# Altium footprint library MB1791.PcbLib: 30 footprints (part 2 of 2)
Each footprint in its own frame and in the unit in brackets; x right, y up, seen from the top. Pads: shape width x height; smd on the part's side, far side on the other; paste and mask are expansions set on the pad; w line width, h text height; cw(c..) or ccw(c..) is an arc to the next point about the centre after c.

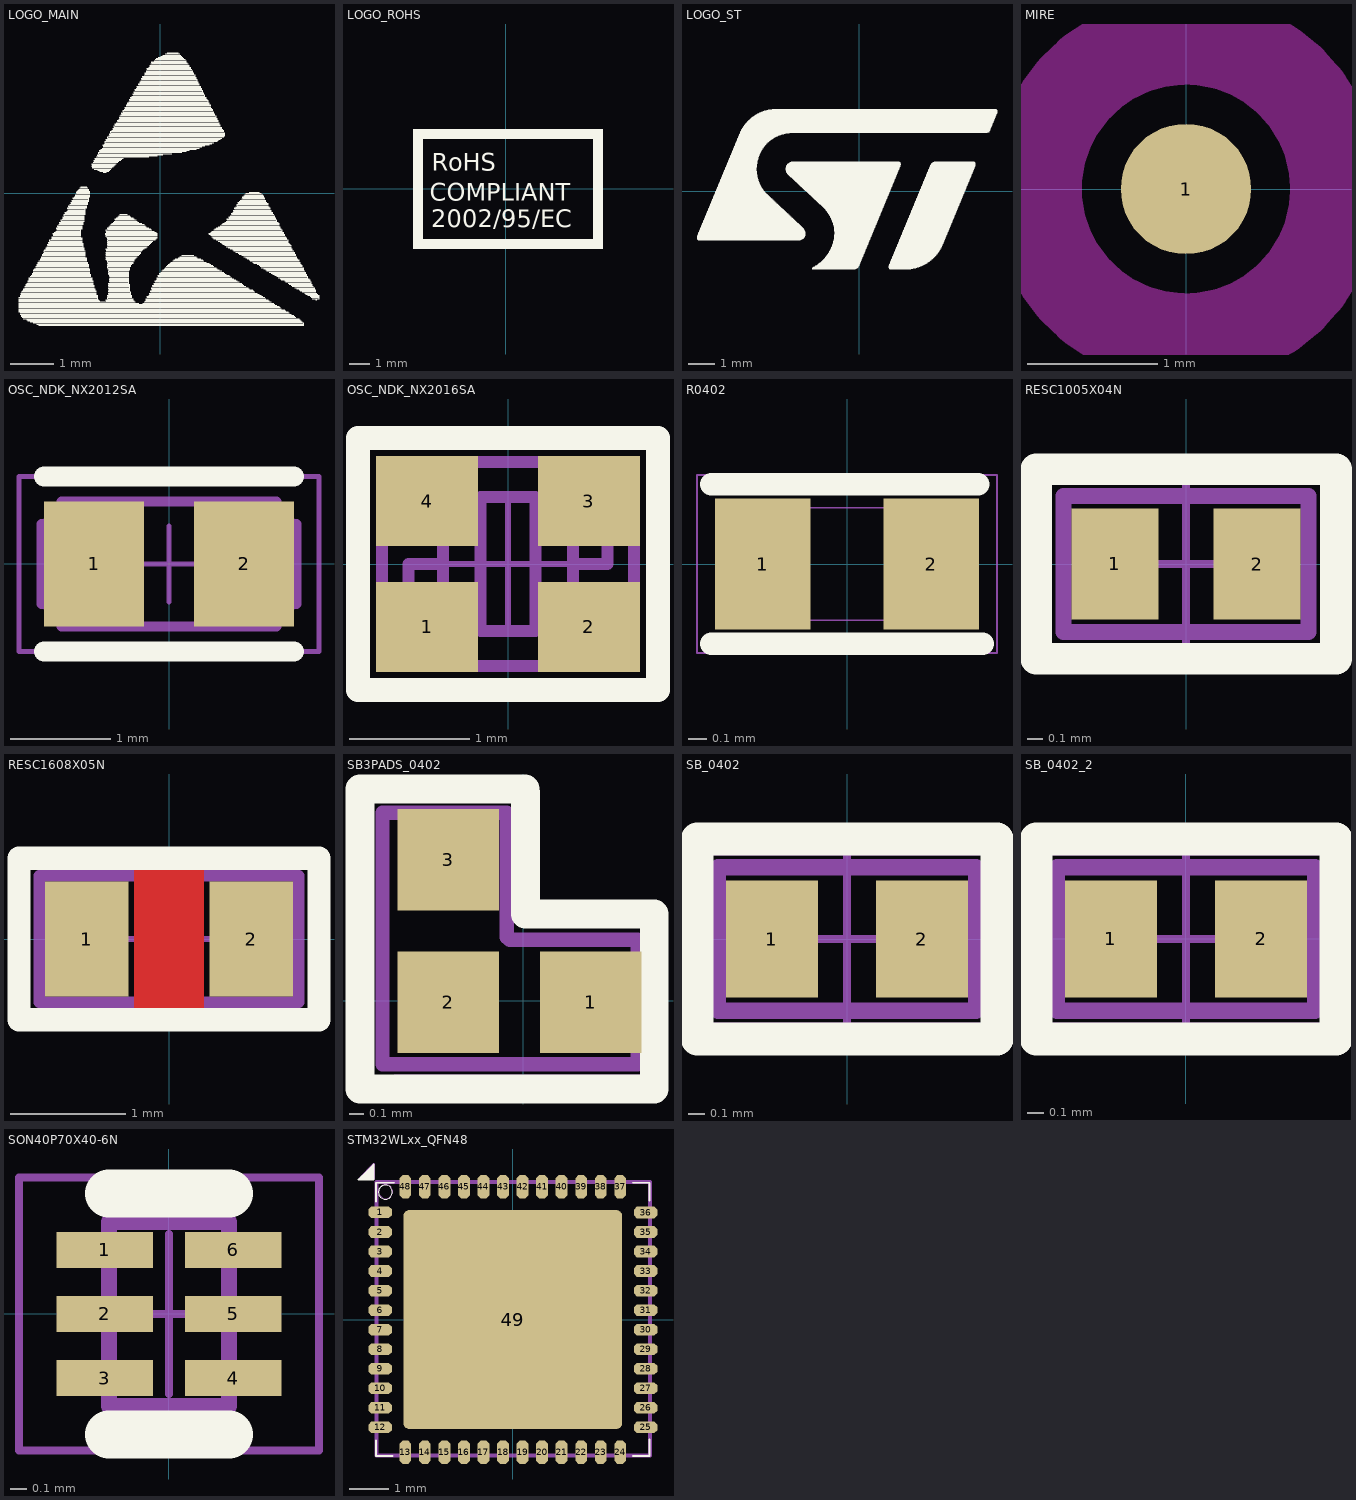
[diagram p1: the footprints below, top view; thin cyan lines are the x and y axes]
## LOGO_MAIN [mm]
Top Overlay:
  drawing of 674 lines, arcs and shapes, not listed

## LOGO_ROHS [mm]
Top Overlay:
  region: 4.872,-3.025 4.872,2.975 4.372,2.975 4.372,-3.025
  region: -4.127,-3.025 -4.127,2.975 -4.627,2.975 -4.627,-3.025
  rectangle: -4.625,2.475 4.375,2.975
  rectangle: -4.625,-3.024 4.375,-2.524
  text "2002/95/EC" at -3.725,-2.225 h1.5
  text "COMPLIANT" at -3.8,-0.9 h1.5
  text "RoHS" at -3.7,0.6 h1.5

## LOGO_ST [mm]
Top Overlay:
  drawing of 1036 lines, arcs and shapes, not listed

## MIRE [mm] "Fiducial Target Round , Pad 1.0mm, Keepout 3mm"
height 0.035
pads (1):
  round 1 smd: 1(0,0)
Top Layer keep-out:
  circle w0.7: c0,0 r1.15
3D body: height 0.04, standoff 0, extent -0.499,-0.499 0.499,0.499

## OSC_NDK_NX2012SA [mm] "Crystal, 2-Leads, Body 2.05x1.20x0.55mm (Tol:-/+0.05)"
height 0.55
pads (2):
  rect 1x1.25 smd: 1(-0.75,0) 2(0.75,0)
Top Overlay:
  lines w0.2: -1.25,-0.875 1.25,-0.875 ; -1.25,0.875 1.25,0.875
Top Assembly:
  lines w0.1: -1.275,-0.4 cw(c-1.275,-0.6) -1.077,-0.625 1.077,-0.625 cw(c1.275,-0.6) 1.275,-0.4 1.275,0.4 cw(c1.275,0.6) 1.077,0.625 -1.077,0.625 cw(c-1.275,0.6) -1.275,0.4 -1.275,-0.4
Mechanical 17:
  lines w0.05: -0.381,0 0.381,0 ; 0,-0.381 0,0.381 ; -1.5,-0.875 1.5,-0.875 1.5,0.875 -1.5,0.875 -1.5,-0.875
3D body: height 0.55, standoff 0, extent -1.038,-0.625 1.025,0.625

## OSC_NDK_NX2016SA [mm] "Crystal, 4-Leads, Body 2.10x1.61x0.50mm (max), Pitch 1.35x1.05mm"
height 0.45
pads (4):
  rect 0.85x0.75 smd: 1(-0.675,-0.525) 2(0.675,-0.525) 3(0.675,0.525) 4(-0.675,0.525)
Top Overlay:
  lines w0.2: -1.25,-1.05 1.25,-1.05 1.25,1.05 -1.25,1.05 -1.25,-1.05
  text "." at -1.475,-1.675 h4
Top Assembly:
  lines w0.1: -0.83,-0.45 -0.83,0 -0.54,0 ; -0.54,-0.3 -0.54,0.3 ; 0.54,-0.3 0.54,0.3 ; 0.54,0 0.83,0 0.83,0.45 ; -1.05,-0.65 cw(c-1.05,-0.85) -0.85,-0.85 0.85,-0.85 cw(c1.05,-0.85) 1.05,-0.65 1.05,0.65 cw(c1.05,0.85) 0.85,0.85 -0.85,0.85 cw(c-1.05,0.85) -1.05,0.65 -1.05,-0.65 ; -0.23,-0.56 -0.23,0.56 0.23,0.56 0.23,-0.56 -0.23,-0.56
  text "." at -0.7,-0.7 h3
Mechanical 17:
  lines w0.05: -0.5,0 0.5,0 ; 0,-0.5 0,0.5 ; -1.25,-1.05 1.25,-1.05 1.25,1.05 -1.25,1.05 -1.25,-1.05
3D body "OSC_NDK_NX2016SA.STEP": height 0.5, standoff 0, extent -1,-0.8 1,0.8

## R0402 [mm]
height 0.4
pads (2):
  rect 0.51x0.7 smd mask+0.05: 1(-0.45,0) 2(0.45,0)
Top Overlay:
  lines w0.12: -0.725,-0.425 0.725,-0.425 ; -0.725,0.425 0.7,0.425
Top Assembly:
  lines w0.01: -0.45,-0.3 0.45,-0.3 0.45,0.3 -0.45,0.3 -0.45,-0.3
  text "'.Designator'" at -2,-0.5 h0.75
Mechanical 16:
  lines w0.01: -0.8,-0.475 -0.8,0.475 0.8,0.475 0.8,-0.475 -0.8,-0.475
3D body "R0402.STEP": height 0.34, standoff 0, extent -0.52,-0.3 0.52,0.3
3D body: height 0.4, standoff 0, extent -0.455,-0.305 0.455,0.305

## RESC1005X04N [mm]
pads (2):
  rect 0.55x0.7 smd: 1(-0.45,0) 2(0.45,0)
Top Overlay:
  lines w0.2: -0.95,-0.6 -0.95,0.6 0.95,0.6 0.95,-0.6 -0.95,-0.6
Top Assembly:
  lines w0.1: -0.775,-0.43 -0.775,0.43 0.775,0.43 0.775,-0.43 -0.775,-0.43
  text ".Designator" at 0.45,0.85 h1.25
Mechanical 17:
  lines w0.05: -0.5,0 0.5,0 ; 0,-0.5 0,0.5 ; -0.9,-0.525 -0.9,0.525 0.9,0.525 0.9,-0.525 -0.9,-0.525
3D body "RESC1005X04N.step": height 0.35, standoff 0, extent -0.5,-0.25 0.5,0.25

## RESC1608X05N [mm] "Chip Resistor, 2-Leads, Body 1.60x0.80mm (0603)"
height 0.5
pads (2):
  rect 0.725x1 smd: 1(-0.713,0) 2(0.713,0)
Top Layer:
  pour cut-out: -0.3,0.7 0.3,0.7 0.3,-0.7 -0.3,-0.7
Top Overlay:
  lines w0.2: -1.3,-0.7 1.3,-0.7 1.3,0.7 -1.3,0.7 -1.3,-0.7
Top Assembly:
  lines w0.1: -1.125,-0.55 -1.125,0.55 1.125,0.55 1.125,-0.55 -1.125,-0.55
  text ".Designator" at 0.65,0.4 h1.25
Mechanical 17:
  lines w0.05: -0.5,0 0.5,0 ; 0,-0.5 0,0.5 ; -1.3,-0.7 -1.3,0.7 1.3,0.7 1.3,-0.7 -1.3,-0.7
3D body "RESC1608X05N.step": height 0.45, standoff 0, extent -0.775,-0.425 0.775,0.425

## SB3PADS_0402 [mm] "Solder Bridge 0 Ohm (0402)"
height 0.6
pads (3):
  rect 0.7x0.7 smd: 1(0.466,-0.009) 2(-0.517,-0.009) 3(-0.517,0.974)
Top Overlay:
  lines w0.2: -1.127,1.461 -1.127,-0.609 0.905,-0.609 0.905,0.6 ; -1.127,1.464 0.012,1.464 ; 0.016,0.6 0.88,0.6 ; 0.016,0.611 0.016,1.441
Top Assembly:
  lines w0.1: -0.972,1.291 -0.972,-0.439 0.791,-0.439 0.791,0.421 -0.094,0.421 -0.113,0.439 -0.113,1.299 -0.972,1.299
  text ".Designator" at 0.009,3.108 h1.25
Mechanical 17:
  lines w0.05: -0.884,-0.534 0.916,-0.534
3D body: height 0.25, standoff 0, extent -0.792,-0.052 -0.292,0.948

## SB_0402 [mm]
pads (2):
  rect 0.55x0.7 smd: 1(-0.45,0) 2(0.45,0)
Top Overlay:
  lines w0.2: -0.9,-0.6 -0.9,0.6 0.9,0.6 0.9,-0.6 -0.9,-0.6
Top Assembly:
  lines w0.1: -0.775,-0.43 -0.775,0.43 0.775,0.43 0.775,-0.43 -0.775,-0.43
  text ".Designator" at -0.775,0.43 h1.25
Mechanical 17:
  lines w0.05: -0.5,0 0.5,0 ; 0,-0.5 0,0.5 ; -0.9,-0.525 -0.9,0.525 0.9,0.525 0.9,-0.525 -0.9,-0.525
3D body: height 0.25, standoff 0, extent -0.5,-0.25 0.5,0.25

## SB_0402_2 [mm]
pads (2):
  rect 0.55x0.7 smd: 1(-0.45,0) 2(0.45,0)
Top Overlay:
  lines w0.2: -0.9,-0.6 0.9,-0.6 0.9,0.6 -0.9,0.6 -0.9,-0.6
Top Assembly:
  lines w0.1: -0.775,-0.43 0.775,-0.43 0.775,0.43 -0.775,0.43 -0.775,-0.43
  text ".Designator" at -1.1,0.4 h1.25
Mechanical 17:
  lines w0.05: -0.5,0 0.5,0 ; 0,-0.5 0,0.5 ; -0.9,-0.525 0.9,-0.525 0.9,0.525 -0.9,0.525 -0.9,-0.525
3D body: height 0.25, standoff 0, extent -0.5,-0.25 0.5,0.25

## SON40P70X40-6N [mm] "SON, 6-Leads, Body 1.10x0.70mm, Pitch 0.40mm"
height 0.4
pads (6):
  rect 0.6x0.225 smd: 1(-0.4,0.4) 2(-0.4,0) 3(-0.4,-0.4) 4(0.4,-0.4) 5(0.4,0) 6(0.4,0.4)
Top Overlay:
  lines w0.3: -0.375,-0.75 0.375,-0.75 ; -0.375,0.75 0.375,0.75
  text "." at -1.2,0.9 h4
Top Assembly:
  lines w0.1: -0.375,-0.575 0.375,-0.575 0.375,0.575 -0.375,0.575 -0.375,-0.575
  text ".Designator" at -0.6,-0.65 h1.25
  text "." at -0.325,0.55 h4
Mechanical 17:
  lines w0.05: -0.5,0 0.5,0 ; 0,-0.5 0,0.5 ; -0.935,-0.85 0.935,-0.85 0.935,0.85 -0.935,0.85 -0.935,-0.85
3D body "SON40P70X40-6N.step": height 0.4, standoff 0, extent -0.376,-0.575 0.376,0.575

## STM32WLxx_QFN48 [mm] "QFN48 7x7x0.55mm pitch 0.5mm"
height 0.55
pads (49):
  oct 0.6x0.3 smd mask+0.06: 1(-3.398,2.746) 2(-3.398,2.239) 3(-3.398,1.739) 4(-3.398,1.239) 5(-3.398,0.739) 6(-3.398,0.239) 7(-3.398,-0.261) 8(-3.398,-0.761) 9(-3.398,-1.261) 10(-3.398,-1.761) 11(-3.398,-2.261) 12(-3.398,-2.761) 25(3.398,-2.761) 26(3.398,-2.261) 27(3.398,-1.761) 28(3.398,-1.261) 29(3.398,-0.761) 30(3.398,-0.261) 31(3.398,0.239) 32(3.398,0.739) 33(3.398,1.239) 34(3.398,1.739) 35(3.398,2.239) 36(3.398,2.739)
  oct 0.3x0.6 smd mask+0.06: 13(-2.752,-3.399) 14(-2.252,-3.399) 15(-1.752,-3.399) 16(-1.252,-3.399) 17(-0.752,-3.399) 18(-0.252,-3.399) 19(0.248,-3.399) 20(0.748,-3.399) 21(1.248,-3.399) 22(1.748,-3.399) 23(2.248,-3.399) 24(2.748,-3.399) 37(2.748,3.399) 38(2.248,3.399) 39(1.748,3.399) 40(1.248,3.399) 41(0.748,3.399) 42(0.248,3.399) 43(-0.252,3.399) 44(-0.752,3.399) 45(-1.252,3.399) 46(-1.752,3.399) 47(-2.252,3.399) 48(-2.752,3.399)
  rrect5% 5.6x5.6 smd paste-3 mask+0.08: 49(0,0)
Top Overlay:
  circle w0.025: c-3.263,3.258 r0.18
  lines w0.025: -3.502,-3.103 -3.502,-3.499 -3.079,-3.499 ; -3.502,3.489 -3.502,3.501 ; 3.077,3.501 3.498,3.501 ; 3.498,-3.499 3.498,-3.067
  lines w0.05: -3.869,3.634 -3.565,3.634 ; -3.869,3.659 -3.565,3.659 ; -3.793,3.583 -3.607,3.785 ; -3.59,3.608 -3.895,3.608 ; -3.59,3.684 -3.692,3.684 -3.615,3.659 -3.59,3.735 -3.895,3.583 -3.59,3.583 -3.59,3.924 -3.844,3.634 -3.565,3.888 -3.819,3.608 -3.895,3.608 ; -3.502,-3.103 -3.502,-3.499 -3.079,-3.499 ; -3.502,3.019 -3.502,3.489 ; -3.502,3.501 -3.044,3.501 ; 3.077,-3.499 3.498,-3.499 3.498,-3.067 ; 3.077,3.501 3.498,3.501 3.498,3.044 ; -3.895,3.608 -3.565,3.964 ; -3.565,3.964 -3.565,3.583 -3.946,3.583 -3.565,3.964
Top Paste:
  rectangle: 1.091,-2.488 2.541,-1.038
  rectangle: -0.712,-2.488 0.738,-1.038
  rectangle: -2.492,-2.488 -1.042,-1.038
  rectangle: -2.492,-0.71 -1.042,0.74
  rectangle: -0.712,-0.71 0.738,0.74
  rectangle: 1.092,-0.71 2.542,0.74
  rectangle: -2.493,1.064 -1.043,2.514
  rectangle: -0.713,1.064 0.737,2.514
  rectangle: 1.091,1.064 2.541,2.514
Top Assembly:
  circle w0.025: c-3.253,3.276 r0.18
  lines w0.05: -3.86,3.651 -3.555,3.651 ; -3.86,3.676 -3.555,3.676 ; -3.784,3.6 -3.597,3.802 ; -3.58,3.626 -3.885,3.626 ; -3.58,3.702 -3.682,3.702 -3.606,3.676 -3.58,3.753 -3.885,3.6 -3.58,3.6 -3.58,3.941 -3.834,3.651 -3.555,3.905 -3.809,3.626 -3.885,3.626 ; -3.885,3.626 -3.555,3.981 ; -3.555,3.981 -3.555,3.6 -3.936,3.6 -3.555,3.981
  lines w0.1: -3.492,-3.481 -3.07,-3.481 ; -3.492,-3.481 -3.07,-3.481 ; -3.492,-3.481 -3.492,-3.085 ; -3.492,-3.481 -3.492,-3.085 ; -3.492,-3.085 -3.492,3.507 -3.492,3.519 3.087,3.519 ; -3.07,-3.481 3.508,-3.481 ; 3.087,3.519 3.508,3.519 ; 3.087,3.519 3.508,3.519 ; 3.508,-3.481 3.508,-3.05 ; 3.508,-3.481 3.508,-3.05 ; 3.508,-3.05 3.508,3.519
  text ".Designator" at -2.995,3.988 h1.25
3D body "User Library-QFN48_7x7.step": height 0.78, standoff -0.02, extent -3.511,-3.509 3.509,3.511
